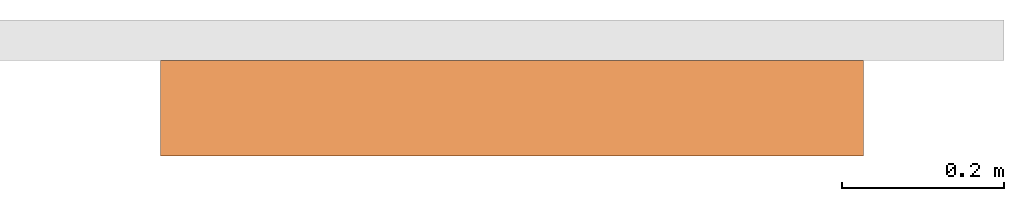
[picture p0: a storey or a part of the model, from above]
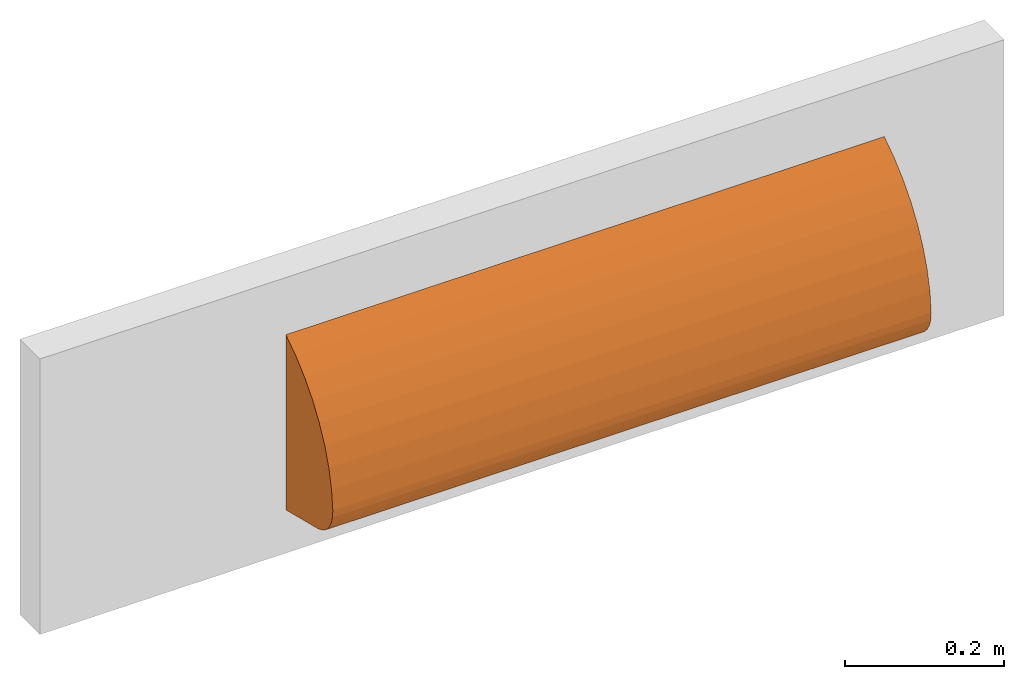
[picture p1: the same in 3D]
Properties of the parts of a building model (IFC2X3)

# File
Description: ViewDefinition [CoordinationView]
Time: 2016-12-12T17:06:32
Written by: The EXPRESS Data Manager Version 5.01.0100.02.64mod : 6 Jun 2012
Made in: 20140709_2115(x64) - Exporter 2014.0.2014.0709 - Default UI
Comment: STEP Physical File produced by: The EXPRESS Data Manager Version 5.01.0100.02.64mod : 6 Jun 2012 * Module: EDMstepFileFactory/EDMstandAlone * Creation date: Mon Dec 12 17:06:32 2016 * Host: BIM-HP * Database: C:\Users\dcole\AppData\Local\Temp\{8D87B0E1-6984-416D-81D8-0F342BFE4887}\ifc * Database version: 5507 * Database creation date: Mon Dec 12 17:06:31 2016 * Schema: IFC2X3 * Model: DataRepository.ifc * Model creation date: Mon Dec 12 17:06:31 2016 * Header model: DataRepository.ifc_HeaderModel * Header model creation date: Mon Dec 12 17:06:31 2016 * EDMuser: sdai-user * EDMgroup: sdai-group * License ID and type: 5605 : Permanent license. Expiry date: * EDMstepFileFactory options: 020000

# IfcProject
LongName: P:\Fastrack\53721_BELL-CHEM\ADDITIONAL DRAWINGS 2016 BIM\IFC\BC101PRD.ifc

# IfcSite, Default
RefLatitude: 42, 24, 53, 508911; RefLongitude: -71, -15, -29, -58837; RefElevation: 0 mm

# IfcBuilding
Pset_BuildingCommon - NumberOfStoreys: 1

# IfcBuildingStorey, Level 1
LongName: Level 1; Elevation: 0 mm
Constraints - Elevation Base: Project Base Point; Elevation: 0 mm
Identity Data - Structural: no; Name: Level 1; Building Story: yes
Dimensions - Computation Height: 0 mm
Graphics - Line Weight: 1; Color: 0; Symbol at End 2 Default: yes; Symbol at End 1 Default: no; Line Pattern: -3000010

# IfcBuildingElementProxy: BC101PRD Dolphin Titan Liner Roll Dispenser, BC101PRD:BC101PRD Dolphin Titan Liner Roll Dispenser:34891
In: Level 1
Material: Paper Towel Unit
Constraints - Moves With Nearby Elements: no; Offset: -110.104 mm; Host: Level : Level 1; Level: Level: Level 1
Dimensions - Volume: 0.0196273 m3; Height: 110mm; Width: 794mm
Phasing - Phase Created: New Construction
Pset_ManufacturerTypeInformation - Manufacturer: Dolphin Solutions Ltd.
Pset_BuildingElementProxyCommon - Reference: BC101PRD Dolphin Titan Liner Roll Dispenser
General - Product Page Link: https://www.dolphinsolutions.co.uk/product/liner-roll-dispenser/; Product Data: Carrying capacity of more than 400kg. An alternitive design embodying strenth, safety and hygiene in a robust construction. Ideal for use in public toilets, washrooms or any area particularly vunerable to vandalism. Aluminium Unit with rounded edges and stainless steel cappings. Liner roll dispenser above the table. Offers your customers a unique service and optimum safety. Hygienic and a customer-friendly solution.
Identity Data - Tel No.: +44 (0) 1424 202 224; Address: Southpoint, Compass Park, Junction Road, Bodiam, TN32 5BS; Fax No.: +44 (0) 1424 205 200; Manufacturer: Dolphin Solutions Ltd.; Model: BC101PRD; Assembly Description: Other Plumbing Fixtures; Email: info@dolphinsolutions.co.uk; Assembly Code: D2010900; URL: www.dolphinsolutions.co.uk; Description: Titan liner roll dispenser

# IfcWallStandardCase: Basic Wall:Wall 1, Basic Wall:Wall 1:3092
In: Level 1
Type - PredefinedType: STANDARD; Material: Default Wall 50 mm
Type - Analytical Properties - Absorptance: 0.1; Roughness: 1
Type - Graphics - Coarse Scale Fill Color: 8454143
Type - Construction - Function: Exterior; Wrapping at Inserts: Do not wrap; Width: 50 mm
Structural - Structural: no; Structural Usage: Non-bearing; Enable Analytical Model: no
Constraints - Top Extension Distance: 0 mm; Base Offset: -175.506 mm; Top is Attached: no; Location Line: Finish Face: Interior; Room Bounding: yes; Base Constraint: Level: Level 1; Related to Mass: no; Base is Attached: no; Top Offset: 0 mm; Unconnected Height: 422.96 mm; Base Extension Distance: 0 mm
Dimensions - Volume: 0.0296072 m3; Length: 1400 mm; Area: 0.592144 m2
Phasing - Phase Created: New Construction
Pset_WallCommon - Reference: Wall 1; LoadBearing: no; ExtendToStructure: no; IsExternal: yes
